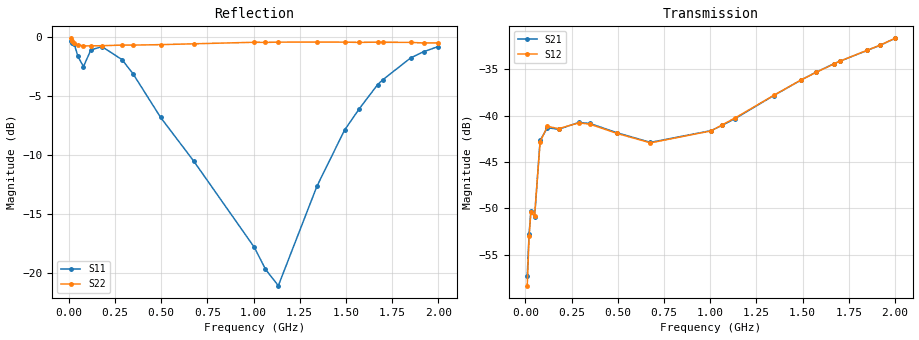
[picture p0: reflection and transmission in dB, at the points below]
!Agilent Technologies,E8364B,MY43040703,A.07.50.48
!Agilent E8364B: A.07.50.48
!Date: Friday, November 12, 2021 03:10:16
!Correction: S11(Full 2 Port(1,2))
!S21(Full 2 Port(1,2))
!S12(Full 2 Port(1,2))
!S22(Full 2 Port(1,2))
!S2P File: Measurements: S11, S21, S12, S22:
# Hz S  dB  R 50
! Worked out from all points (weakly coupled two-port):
!   201 points, 10 MHz to 2 GHz, reference 50 ohm
!   highest |S21| = -31.65 dB at 2 GHz (marker M1); lowest = -57.3 dB at 10 MHz (marker M2)
!   lowest |S11| = -21.1 dB at 1.134 GHz (marker M3), VSWR 1.19, Z = 56.2 + j7.1 ohm
!   |S11| at or under -10 dB: 649.1 MHz to 1.426 GHz (776.6 MHz wide, 74.9 % of centre)
!   |S22| runs from -0.8 to -0.1 dB; largest |S21 - S12| = 0.0025
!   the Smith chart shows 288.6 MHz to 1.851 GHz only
!   S11 on the Smith chart (normalised r, x): 288.6 MHz: 0.43, +1.65; 497.6 MHz: 2.10, -0.99; 1.065 GHz: 0.93, +0.19; 1.493 GHz: 0.43, +0.10; 1.702 GHz: 0.71, +1.44; 1.851 GHz: 5.53, -4.75
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1e7  -0.34 -57.1  -57.28 -175.1  -58.35 -22.6  -0.15 -33.1
1.995e7  -0.56 -97.4  -52.78 78.4  -53.01 90.2  -0.36 -61.5
2.99e7  -0.63 -125.8  -50.29 71.2  -50.37 74.4  -0.52 -84.4
4.98e7  -1.68 -167.8  -50.91 52.5  -50.82 47.5  -0.70 -116.2
7.965e7  -2.54 -175.2  -42.66 39.9  -42.81 39.5  -0.79 -144.6
1.1945e8  -1.14 155.6  -41.29 -1.3  -41.14 -1.7  -0.78 -167.0
1.7915e8  -0.84 118.1  -41.47 -26.6  -41.40 -25.8  -0.77 170.8
2.886e8  -1.95 60.0  -40.73 -74.0  -40.77 -72.7  -0.72 142.1
3.483e8  -3.15 32.3  -40.83 -96.0  -40.91 -95.8  -0.72 128.6
4.9755e8  -6.84 -24.2  -41.85 -145.6  -41.92 -145.8  -0.68 97.8
6.7665e8  -10.53 -74.7  -42.88 165.7  -42.93 166.4  -0.61 63.1
1.005e9  -17.83 151.1  -41.61 86.1  -41.64 86.4  -0.48 2.0
1.0647e9  -19.67 106.1  -41.04 70.7  -40.99 70.5  -0.49 -9.0
1.13435e9  -21.06 45.0  -40.32 51.5  -40.25 51.6  -0.47 -21.8
1.3433e9  -12.65 -112.9  -37.83 -10.4  -37.81 -10.3  -0.46 -59.7
1.49255e9  -7.91 166.2  -36.14 -58.5  -36.13 -58.5  -0.47 -86.8
1.57215e9  -6.11 125.8  -35.31 -85.5  -35.33 -85.5  -0.49 -101.2
1.67165e9  -4.06 76.1  -34.37 -119.5  -34.39 -119.3  -0.47 -119.2
1.7015e9  -3.63 61.5  -34.12 -129.9  -34.12 -130.0  -0.48 -124.5
1.85075e9  -1.80 -10.3  -32.94 178.2  -32.93 178.1  -0.49 -151.2
1.9204e9  -1.28 -43.2  -32.40 153.7  -32.37 153.8  -0.54 -163.6
2e9  -0.84 -80.7  -31.65 124.8  -31.65 124.9  -0.53 -177.9
